# Generated by FakeRAM 2.0
VERSION 5.7 ;
BUSBITCHARS "[]" ;
PROPERTYDEFINITIONS
  MACRO width INTEGER ;
  MACRO depth INTEGER ;
  MACRO banks INTEGER ;
END PROPERTYDEFINITIONS
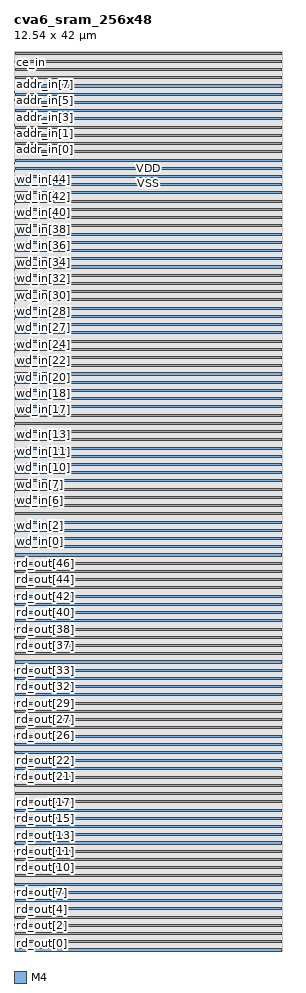
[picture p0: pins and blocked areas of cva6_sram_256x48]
MACRO cva6_sram_256x48
  PROPERTY width 48 ;
  PROPERTY depth 256 ;
  PROPERTY banks 1 ;
  FOREIGN cva6_sram_256x48 0 0 ;
  SYMMETRY X Y R90 ;
  SIZE 12.5400 BY 42.0000 ;
  CLASS BLOCK ;
  PIN rd_out[0]
    DIRECTION OUTPUT ;
    USE SIGNAL ;
    PORT
      LAYER M4 ;
      RECT 0.00000 0.04800 0.02400 0.07200 ;
    END
  END rd_out[0]
  PIN rd_out[1]
    DIRECTION OUTPUT ;
    USE SIGNAL ;
    PORT
      LAYER M4 ;
      RECT 0.00000 0.43200 0.02400 0.45600 ;
    END
  END rd_out[1]
  PIN rd_out[2]
    DIRECTION OUTPUT ;
    USE SIGNAL ;
    PORT
      LAYER M4 ;
      RECT 0.00000 0.81600 0.02400 0.84000 ;
    END
  END rd_out[2]
  PIN rd_out[3]
    DIRECTION OUTPUT ;
    USE SIGNAL ;
    PORT
      LAYER M4 ;
      RECT 0.00000 1.20000 0.02400 1.22400 ;
    END
  END rd_out[3]
  PIN rd_out[4]
    DIRECTION OUTPUT ;
    USE SIGNAL ;
    PORT
      LAYER M4 ;
      RECT 0.00000 1.58400 0.02400 1.60800 ;
    END
  END rd_out[4]
  PIN rd_out[5]
    DIRECTION OUTPUT ;
    USE SIGNAL ;
    PORT
      LAYER M4 ;
      RECT 0.00000 1.96800 0.02400 1.99200 ;
    END
  END rd_out[5]
  PIN rd_out[6]
    DIRECTION OUTPUT ;
    USE SIGNAL ;
    PORT
      LAYER M4 ;
      RECT 0.00000 2.35200 0.02400 2.37600 ;
    END
  END rd_out[6]
  PIN rd_out[7]
    DIRECTION OUTPUT ;
    USE SIGNAL ;
    PORT
      LAYER M4 ;
      RECT 0.00000 2.73600 0.02400 2.76000 ;
    END
  END rd_out[7]
  PIN rd_out[8]
    DIRECTION OUTPUT ;
    USE SIGNAL ;
    PORT
      LAYER M4 ;
      RECT 0.00000 3.12000 0.02400 3.14400 ;
    END
  END rd_out[8]
  PIN rd_out[9]
    DIRECTION OUTPUT ;
    USE SIGNAL ;
    PORT
      LAYER M4 ;
      RECT 0.00000 3.50400 0.02400 3.52800 ;
    END
  END rd_out[9]
  PIN rd_out[10]
    DIRECTION OUTPUT ;
    USE SIGNAL ;
    PORT
      LAYER M4 ;
      RECT 0.00000 3.88800 0.02400 3.91200 ;
    END
  END rd_out[10]
  PIN rd_out[11]
    DIRECTION OUTPUT ;
    USE SIGNAL ;
    PORT
      LAYER M4 ;
      RECT 0.00000 4.27200 0.02400 4.29600 ;
    END
  END rd_out[11]
  PIN rd_out[12]
    DIRECTION OUTPUT ;
    USE SIGNAL ;
    PORT
      LAYER M4 ;
      RECT 0.00000 4.65600 0.02400 4.68000 ;
    END
  END rd_out[12]
  PIN rd_out[13]
    DIRECTION OUTPUT ;
    USE SIGNAL ;
    PORT
      LAYER M4 ;
      RECT 0.00000 5.04000 0.02400 5.06400 ;
    END
  END rd_out[13]
  PIN rd_out[14]
    DIRECTION OUTPUT ;
    USE SIGNAL ;
    PORT
      LAYER M4 ;
      RECT 0.00000 5.42400 0.02400 5.44800 ;
    END
  END rd_out[14]
  PIN rd_out[15]
    DIRECTION OUTPUT ;
    USE SIGNAL ;
    PORT
      LAYER M4 ;
      RECT 0.00000 5.80800 0.02400 5.83200 ;
    END
  END rd_out[15]
  PIN rd_out[16]
    DIRECTION OUTPUT ;
    USE SIGNAL ;
    PORT
      LAYER M4 ;
      RECT 0.00000 6.19200 0.02400 6.21600 ;
    END
  END rd_out[16]
  PIN rd_out[17]
    DIRECTION OUTPUT ;
    USE SIGNAL ;
    PORT
      LAYER M4 ;
      RECT 0.00000 6.57600 0.02400 6.60000 ;
    END
  END rd_out[17]
  PIN rd_out[18]
    DIRECTION OUTPUT ;
    USE SIGNAL ;
    PORT
      LAYER M4 ;
      RECT 0.00000 6.96000 0.02400 6.98400 ;
    END
  END rd_out[18]
  PIN rd_out[19]
    DIRECTION OUTPUT ;
    USE SIGNAL ;
    PORT
      LAYER M4 ;
      RECT 0.00000 7.34400 0.02400 7.36800 ;
    END
  END rd_out[19]
  PIN rd_out[20]
    DIRECTION OUTPUT ;
    USE SIGNAL ;
    PORT
      LAYER M4 ;
      RECT 0.00000 7.72800 0.02400 7.75200 ;
    END
  END rd_out[20]
  PIN rd_out[21]
    DIRECTION OUTPUT ;
    USE SIGNAL ;
    PORT
      LAYER M4 ;
      RECT 0.00000 8.11200 0.02400 8.13600 ;
    END
  END rd_out[21]
  PIN rd_out[22]
    DIRECTION OUTPUT ;
    USE SIGNAL ;
    PORT
      LAYER M4 ;
      RECT 0.00000 8.49600 0.02400 8.52000 ;
    END
  END rd_out[22]
  PIN rd_out[23]
    DIRECTION OUTPUT ;
    USE SIGNAL ;
    PORT
      LAYER M4 ;
      RECT 0.00000 8.88000 0.02400 8.90400 ;
    END
  END rd_out[23]
  PIN rd_out[24]
    DIRECTION OUTPUT ;
    USE SIGNAL ;
    PORT
      LAYER M4 ;
      RECT 0.00000 9.26400 0.02400 9.28800 ;
    END
  END rd_out[24]
  PIN rd_out[25]
    DIRECTION OUTPUT ;
    USE SIGNAL ;
    PORT
      LAYER M4 ;
      RECT 0.00000 9.64800 0.02400 9.67200 ;
    END
  END rd_out[25]
  PIN rd_out[26]
    DIRECTION OUTPUT ;
    USE SIGNAL ;
    PORT
      LAYER M4 ;
      RECT 0.00000 10.03200 0.02400 10.05600 ;
    END
  END rd_out[26]
  PIN rd_out[27]
    DIRECTION OUTPUT ;
    USE SIGNAL ;
    PORT
      LAYER M4 ;
      RECT 0.00000 10.41600 0.02400 10.44000 ;
    END
  END rd_out[27]
  PIN rd_out[28]
    DIRECTION OUTPUT ;
    USE SIGNAL ;
    PORT
      LAYER M4 ;
      RECT 0.00000 10.80000 0.02400 10.82400 ;
    END
  END rd_out[28]
  PIN rd_out[29]
    DIRECTION OUTPUT ;
    USE SIGNAL ;
    PORT
      LAYER M4 ;
      RECT 0.00000 11.18400 0.02400 11.20800 ;
    END
  END rd_out[29]
  PIN rd_out[30]
    DIRECTION OUTPUT ;
    USE SIGNAL ;
    PORT
      LAYER M4 ;
      RECT 0.00000 11.56800 0.02400 11.59200 ;
    END
  END rd_out[30]
  PIN rd_out[31]
    DIRECTION OUTPUT ;
    USE SIGNAL ;
    PORT
      LAYER M4 ;
      RECT 0.00000 11.95200 0.02400 11.97600 ;
    END
  END rd_out[31]
  PIN rd_out[32]
    DIRECTION OUTPUT ;
    USE SIGNAL ;
    PORT
      LAYER M4 ;
      RECT 0.00000 12.33600 0.02400 12.36000 ;
    END
  END rd_out[32]
  PIN rd_out[33]
    DIRECTION OUTPUT ;
    USE SIGNAL ;
    PORT
      LAYER M4 ;
      RECT 0.00000 12.72000 0.02400 12.74400 ;
    END
  END rd_out[33]
  PIN rd_out[34]
    DIRECTION OUTPUT ;
    USE SIGNAL ;
    PORT
      LAYER M4 ;
      RECT 0.00000 13.10400 0.02400 13.12800 ;
    END
  END rd_out[34]
  PIN rd_out[35]
    DIRECTION OUTPUT ;
    USE SIGNAL ;
    PORT
      LAYER M4 ;
      RECT 0.00000 13.48800 0.02400 13.51200 ;
    END
  END rd_out[35]
  PIN rd_out[36]
    DIRECTION OUTPUT ;
    USE SIGNAL ;
    PORT
      LAYER M4 ;
      RECT 0.00000 13.87200 0.02400 13.89600 ;
    END
  END rd_out[36]
  PIN rd_out[37]
    DIRECTION OUTPUT ;
    USE SIGNAL ;
    PORT
      LAYER M4 ;
      RECT 0.00000 14.25600 0.02400 14.28000 ;
    END
  END rd_out[37]
  PIN rd_out[38]
    DIRECTION OUTPUT ;
    USE SIGNAL ;
    PORT
      LAYER M4 ;
      RECT 0.00000 14.64000 0.02400 14.66400 ;
    END
  END rd_out[38]
  PIN rd_out[39]
    DIRECTION OUTPUT ;
    USE SIGNAL ;
    PORT
      LAYER M4 ;
      RECT 0.00000 15.02400 0.02400 15.04800 ;
    END
  END rd_out[39]
  PIN rd_out[40]
    DIRECTION OUTPUT ;
    USE SIGNAL ;
    PORT
      LAYER M4 ;
      RECT 0.00000 15.40800 0.02400 15.43200 ;
    END
  END rd_out[40]
  PIN rd_out[41]
    DIRECTION OUTPUT ;
    USE SIGNAL ;
    PORT
      LAYER M4 ;
      RECT 0.00000 15.79200 0.02400 15.81600 ;
    END
  END rd_out[41]
  PIN rd_out[42]
    DIRECTION OUTPUT ;
    USE SIGNAL ;
    PORT
      LAYER M4 ;
      RECT 0.00000 16.17600 0.02400 16.20000 ;
    END
  END rd_out[42]
  PIN rd_out[43]
    DIRECTION OUTPUT ;
    USE SIGNAL ;
    PORT
      LAYER M4 ;
      RECT 0.00000 16.56000 0.02400 16.58400 ;
    END
  END rd_out[43]
  PIN rd_out[44]
    DIRECTION OUTPUT ;
    USE SIGNAL ;
    PORT
      LAYER M4 ;
      RECT 0.00000 16.94400 0.02400 16.96800 ;
    END
  END rd_out[44]
  PIN rd_out[45]
    DIRECTION OUTPUT ;
    USE SIGNAL ;
    PORT
      LAYER M4 ;
      RECT 0.00000 17.32800 0.02400 17.35200 ;
    END
  END rd_out[45]
  PIN rd_out[46]
    DIRECTION OUTPUT ;
    USE SIGNAL ;
    PORT
      LAYER M4 ;
      RECT 0.00000 17.71200 0.02400 17.73600 ;
    END
  END rd_out[46]
  PIN rd_out[47]
    DIRECTION OUTPUT ;
    USE SIGNAL ;
    PORT
      LAYER M4 ;
      RECT 0.00000 18.09600 0.02400 18.12000 ;
    END
  END rd_out[47]
  PIN wd_in[0]
    DIRECTION INPUT ;
    USE SIGNAL ;
    PORT
      LAYER M4 ;
      RECT 0.00000 18.72000 0.02400 18.74400 ;
    END
  END wd_in[0]
  PIN wd_in[1]
    DIRECTION INPUT ;
    USE SIGNAL ;
    PORT
      LAYER M4 ;
      RECT 0.00000 19.10400 0.02400 19.12800 ;
    END
  END wd_in[1]
  PIN wd_in[2]
    DIRECTION INPUT ;
    USE SIGNAL ;
    PORT
      LAYER M4 ;
      RECT 0.00000 19.48800 0.02400 19.51200 ;
    END
  END wd_in[2]
  PIN wd_in[3]
    DIRECTION INPUT ;
    USE SIGNAL ;
    PORT
      LAYER M4 ;
      RECT 0.00000 19.87200 0.02400 19.89600 ;
    END
  END wd_in[3]
  PIN wd_in[4]
    DIRECTION INPUT ;
    USE SIGNAL ;
    PORT
      LAYER M4 ;
      RECT 0.00000 20.25600 0.02400 20.28000 ;
    END
  END wd_in[4]
  PIN wd_in[5]
    DIRECTION INPUT ;
    USE SIGNAL ;
    PORT
      LAYER M4 ;
      RECT 0.00000 20.64000 0.02400 20.66400 ;
    END
  END wd_in[5]
  PIN wd_in[6]
    DIRECTION INPUT ;
    USE SIGNAL ;
    PORT
      LAYER M4 ;
      RECT 0.00000 21.02400 0.02400 21.04800 ;
    END
  END wd_in[6]
  PIN wd_in[7]
    DIRECTION INPUT ;
    USE SIGNAL ;
    PORT
      LAYER M4 ;
      RECT 0.00000 21.40800 0.02400 21.43200 ;
    END
  END wd_in[7]
  PIN wd_in[8]
    DIRECTION INPUT ;
    USE SIGNAL ;
    PORT
      LAYER M4 ;
      RECT 0.00000 21.79200 0.02400 21.81600 ;
    END
  END wd_in[8]
  PIN wd_in[9]
    DIRECTION INPUT ;
    USE SIGNAL ;
    PORT
      LAYER M4 ;
      RECT 0.00000 22.17600 0.02400 22.20000 ;
    END
  END wd_in[9]
  PIN wd_in[10]
    DIRECTION INPUT ;
    USE SIGNAL ;
    PORT
      LAYER M4 ;
      RECT 0.00000 22.56000 0.02400 22.58400 ;
    END
  END wd_in[10]
  PIN wd_in[11]
    DIRECTION INPUT ;
    USE SIGNAL ;
    PORT
      LAYER M4 ;
      RECT 0.00000 22.94400 0.02400 22.96800 ;
    END
  END wd_in[11]
  PIN wd_in[12]
    DIRECTION INPUT ;
    USE SIGNAL ;
    PORT
      LAYER M4 ;
      RECT 0.00000 23.32800 0.02400 23.35200 ;
    END
  END wd_in[12]
  PIN wd_in[13]
    DIRECTION INPUT ;
    USE SIGNAL ;
    PORT
      LAYER M4 ;
      RECT 0.00000 23.71200 0.02400 23.73600 ;
    END
  END wd_in[13]
  PIN wd_in[14]
    DIRECTION INPUT ;
    USE SIGNAL ;
    PORT
      LAYER M4 ;
      RECT 0.00000 24.09600 0.02400 24.12000 ;
    END
  END wd_in[14]
  PIN wd_in[15]
    DIRECTION INPUT ;
    USE SIGNAL ;
    PORT
      LAYER M4 ;
      RECT 0.00000 24.48000 0.02400 24.50400 ;
    END
  END wd_in[15]
  PIN wd_in[16]
    DIRECTION INPUT ;
    USE SIGNAL ;
    PORT
      LAYER M4 ;
      RECT 0.00000 24.86400 0.02400 24.88800 ;
    END
  END wd_in[16]
  PIN wd_in[17]
    DIRECTION INPUT ;
    USE SIGNAL ;
    PORT
      LAYER M4 ;
      RECT 0.00000 25.24800 0.02400 25.27200 ;
    END
  END wd_in[17]
  PIN wd_in[18]
    DIRECTION INPUT ;
    USE SIGNAL ;
    PORT
      LAYER M4 ;
      RECT 0.00000 25.63200 0.02400 25.65600 ;
    END
  END wd_in[18]
  PIN wd_in[19]
    DIRECTION INPUT ;
    USE SIGNAL ;
    PORT
      LAYER M4 ;
      RECT 0.00000 26.01600 0.02400 26.04000 ;
    END
  END wd_in[19]
  PIN wd_in[20]
    DIRECTION INPUT ;
    USE SIGNAL ;
    PORT
      LAYER M4 ;
      RECT 0.00000 26.40000 0.02400 26.42400 ;
    END
  END wd_in[20]
  PIN wd_in[21]
    DIRECTION INPUT ;
    USE SIGNAL ;
    PORT
      LAYER M4 ;
      RECT 0.00000 26.78400 0.02400 26.80800 ;
    END
  END wd_in[21]
  PIN wd_in[22]
    DIRECTION INPUT ;
    USE SIGNAL ;
    PORT
      LAYER M4 ;
      RECT 0.00000 27.16800 0.02400 27.19200 ;
    END
  END wd_in[22]
  PIN wd_in[23]
    DIRECTION INPUT ;
    USE SIGNAL ;
    PORT
      LAYER M4 ;
      RECT 0.00000 27.55200 0.02400 27.57600 ;
    END
  END wd_in[23]
  PIN wd_in[24]
    DIRECTION INPUT ;
    USE SIGNAL ;
    PORT
      LAYER M4 ;
      RECT 0.00000 27.93600 0.02400 27.96000 ;
    END
  END wd_in[24]
  PIN wd_in[25]
    DIRECTION INPUT ;
    USE SIGNAL ;
    PORT
      LAYER M4 ;
      RECT 0.00000 28.32000 0.02400 28.34400 ;
    END
  END wd_in[25]
  PIN wd_in[26]
    DIRECTION INPUT ;
    USE SIGNAL ;
    PORT
      LAYER M4 ;
      RECT 0.00000 28.70400 0.02400 28.72800 ;
    END
  END wd_in[26]
  PIN wd_in[27]
    DIRECTION INPUT ;
    USE SIGNAL ;
    PORT
      LAYER M4 ;
      RECT 0.00000 29.08800 0.02400 29.11200 ;
    END
  END wd_in[27]
  PIN wd_in[28]
    DIRECTION INPUT ;
    USE SIGNAL ;
    PORT
      LAYER M4 ;
      RECT 0.00000 29.47200 0.02400 29.49600 ;
    END
  END wd_in[28]
  PIN wd_in[29]
    DIRECTION INPUT ;
    USE SIGNAL ;
    PORT
      LAYER M4 ;
      RECT 0.00000 29.85600 0.02400 29.88000 ;
    END
  END wd_in[29]
  PIN wd_in[30]
    DIRECTION INPUT ;
    USE SIGNAL ;
    PORT
      LAYER M4 ;
      RECT 0.00000 30.24000 0.02400 30.26400 ;
    END
  END wd_in[30]
  PIN wd_in[31]
    DIRECTION INPUT ;
    USE SIGNAL ;
    PORT
      LAYER M4 ;
      RECT 0.00000 30.62400 0.02400 30.64800 ;
    END
  END wd_in[31]
  PIN wd_in[32]
    DIRECTION INPUT ;
    USE SIGNAL ;
    PORT
      LAYER M4 ;
      RECT 0.00000 31.00800 0.02400 31.03200 ;
    END
  END wd_in[32]
  PIN wd_in[33]
    DIRECTION INPUT ;
    USE SIGNAL ;
    PORT
      LAYER M4 ;
      RECT 0.00000 31.39200 0.02400 31.41600 ;
    END
  END wd_in[33]
  PIN wd_in[34]
    DIRECTION INPUT ;
    USE SIGNAL ;
    PORT
      LAYER M4 ;
      RECT 0.00000 31.77600 0.02400 31.80000 ;
    END
  END wd_in[34]
  PIN wd_in[35]
    DIRECTION INPUT ;
    USE SIGNAL ;
    PORT
      LAYER M4 ;
      RECT 0.00000 32.16000 0.02400 32.18400 ;
    END
  END wd_in[35]
  PIN wd_in[36]
    DIRECTION INPUT ;
    USE SIGNAL ;
    PORT
      LAYER M4 ;
      RECT 0.00000 32.54400 0.02400 32.56800 ;
    END
  END wd_in[36]
  PIN wd_in[37]
    DIRECTION INPUT ;
    USE SIGNAL ;
    PORT
      LAYER M4 ;
      RECT 0.00000 32.92800 0.02400 32.95200 ;
    END
  END wd_in[37]
  PIN wd_in[38]
    DIRECTION INPUT ;
    USE SIGNAL ;
    PORT
      LAYER M4 ;
      RECT 0.00000 33.31200 0.02400 33.33600 ;
    END
  END wd_in[38]
  PIN wd_in[39]
    DIRECTION INPUT ;
    USE SIGNAL ;
    PORT
      LAYER M4 ;
      RECT 0.00000 33.69600 0.02400 33.72000 ;
    END
  END wd_in[39]
  PIN wd_in[40]
    DIRECTION INPUT ;
    USE SIGNAL ;
    PORT
      LAYER M4 ;
      RECT 0.00000 34.08000 0.02400 34.10400 ;
    END
  END wd_in[40]
  PIN wd_in[41]
    DIRECTION INPUT ;
    USE SIGNAL ;
    PORT
      LAYER M4 ;
      RECT 0.00000 34.46400 0.02400 34.48800 ;
    END
  END wd_in[41]
  PIN wd_in[42]
    DIRECTION INPUT ;
    USE SIGNAL ;
    PORT
      LAYER M4 ;
      RECT 0.00000 34.84800 0.02400 34.87200 ;
    END
  END wd_in[42]
  PIN wd_in[43]
    DIRECTION INPUT ;
    USE SIGNAL ;
    PORT
      LAYER M4 ;
      RECT 0.00000 35.23200 0.02400 35.25600 ;
    END
  END wd_in[43]
  PIN wd_in[44]
    DIRECTION INPUT ;
    USE SIGNAL ;
    PORT
      LAYER M4 ;
      RECT 0.00000 35.61600 0.02400 35.64000 ;
    END
  END wd_in[44]
  PIN wd_in[45]
    DIRECTION INPUT ;
    USE SIGNAL ;
    PORT
      LAYER M4 ;
      RECT 0.00000 36.00000 0.02400 36.02400 ;
    END
  END wd_in[45]
  PIN wd_in[46]
    DIRECTION INPUT ;
    USE SIGNAL ;
    PORT
      LAYER M4 ;
      RECT 0.00000 36.38400 0.02400 36.40800 ;
    END
  END wd_in[46]
  PIN wd_in[47]
    DIRECTION INPUT ;
    USE SIGNAL ;
    PORT
      LAYER M4 ;
      RECT 0.00000 36.76800 0.02400 36.79200 ;
    END
  END wd_in[47]
  PIN addr_in[0]
    DIRECTION INPUT ;
    USE SIGNAL ;
    PORT
      LAYER M4 ;
      RECT 0.00000 37.39200 0.02400 37.41600 ;
    END
  END addr_in[0]
  PIN addr_in[1]
    DIRECTION INPUT ;
    USE SIGNAL ;
    PORT
      LAYER M4 ;
      RECT 0.00000 37.77600 0.02400 37.80000 ;
    END
  END addr_in[1]
  PIN addr_in[2]
    DIRECTION INPUT ;
    USE SIGNAL ;
    PORT
      LAYER M4 ;
      RECT 0.00000 38.16000 0.02400 38.18400 ;
    END
  END addr_in[2]
  PIN addr_in[3]
    DIRECTION INPUT ;
    USE SIGNAL ;
    PORT
      LAYER M4 ;
      RECT 0.00000 38.54400 0.02400 38.56800 ;
    END
  END addr_in[3]
  PIN addr_in[4]
    DIRECTION INPUT ;
    USE SIGNAL ;
    PORT
      LAYER M4 ;
      RECT 0.00000 38.92800 0.02400 38.95200 ;
    END
  END addr_in[4]
  PIN addr_in[5]
    DIRECTION INPUT ;
    USE SIGNAL ;
    PORT
      LAYER M4 ;
      RECT 0.00000 39.31200 0.02400 39.33600 ;
    END
  END addr_in[5]
  PIN addr_in[6]
    DIRECTION INPUT ;
    USE SIGNAL ;
    PORT
      LAYER M4 ;
      RECT 0.00000 39.69600 0.02400 39.72000 ;
    END
  END addr_in[6]
  PIN addr_in[7]
    DIRECTION INPUT ;
    USE SIGNAL ;
    PORT
      LAYER M4 ;
      RECT 0.00000 40.08000 0.02400 40.10400 ;
    END
  END addr_in[7]
  PIN we_in
    DIRECTION INPUT ;
    USE SIGNAL ;
    PORT
      LAYER M4 ;
      RECT 0.00000 40.70400 0.02400 40.72800 ;
    END
  END we_in
  PIN clk
    DIRECTION INPUT ;
    USE SIGNAL ;
    PORT
      LAYER M4 ;
      RECT 0.00000 41.08800 0.02400 41.11200 ;
    END
  END clk
  PIN ce_in
    DIRECTION INPUT ;
    USE SIGNAL ;
    PORT
      LAYER M4 ;
      RECT 0.00000 41.47200 0.02400 41.49600 ;
    END
  END ce_in
  PIN VDD
    DIRECTION INOUT ;
    USE POWER ;
    PORT
      LAYER M4 ;
      RECT 0.04800 0.38400 12.49200 0.48000 ;
      RECT 0.04800 1.15200 12.49200 1.24800 ;
      RECT 0.04800 1.92000 12.49200 2.01600 ;
      RECT 0.04800 2.68800 12.49200 2.78400 ;
      RECT 0.04800 3.45600 12.49200 3.55200 ;
      RECT 0.04800 4.22400 12.49200 4.32000 ;
      RECT 0.04800 4.99200 12.49200 5.08800 ;
      RECT 0.04800 5.76000 12.49200 5.85600 ;
      RECT 0.04800 6.52800 12.49200 6.62400 ;
      RECT 0.04800 7.29600 12.49200 7.39200 ;
      RECT 0.04800 8.06400 12.49200 8.16000 ;
      RECT 0.04800 8.83200 12.49200 8.92800 ;
      RECT 0.04800 9.60000 12.49200 9.69600 ;
      RECT 0.04800 10.36800 12.49200 10.46400 ;
      RECT 0.04800 11.13600 12.49200 11.23200 ;
      RECT 0.04800 11.90400 12.49200 12.00000 ;
      RECT 0.04800 12.67200 12.49200 12.76800 ;
      RECT 0.04800 13.44000 12.49200 13.53600 ;
      RECT 0.04800 14.20800 12.49200 14.30400 ;
      RECT 0.04800 14.97600 12.49200 15.07200 ;
      RECT 0.04800 15.74400 12.49200 15.84000 ;
      RECT 0.04800 16.51200 12.49200 16.60800 ;
      RECT 0.04800 17.28000 12.49200 17.37600 ;
      RECT 0.04800 18.04800 12.49200 18.14400 ;
      RECT 0.04800 18.81600 12.49200 18.91200 ;
      RECT 0.04800 19.58400 12.49200 19.68000 ;
      RECT 0.04800 20.35200 12.49200 20.44800 ;
      RECT 0.04800 21.12000 12.49200 21.21600 ;
      RECT 0.04800 21.88800 12.49200 21.98400 ;
      RECT 0.04800 22.65600 12.49200 22.75200 ;
      RECT 0.04800 23.42400 12.49200 23.52000 ;
      RECT 0.04800 24.19200 12.49200 24.28800 ;
      RECT 0.04800 24.96000 12.49200 25.05600 ;
      RECT 0.04800 25.72800 12.49200 25.82400 ;
      RECT 0.04800 26.49600 12.49200 26.59200 ;
      RECT 0.04800 27.26400 12.49200 27.36000 ;
      RECT 0.04800 28.03200 12.49200 28.12800 ;
      RECT 0.04800 28.80000 12.49200 28.89600 ;
      RECT 0.04800 29.56800 12.49200 29.66400 ;
      RECT 0.04800 30.33600 12.49200 30.43200 ;
      RECT 0.04800 31.10400 12.49200 31.20000 ;
      RECT 0.04800 31.87200 12.49200 31.96800 ;
      RECT 0.04800 32.64000 12.49200 32.73600 ;
      RECT 0.04800 33.40800 12.49200 33.50400 ;
      RECT 0.04800 34.17600 12.49200 34.27200 ;
      RECT 0.04800 34.94400 12.49200 35.04000 ;
      RECT 0.04800 35.71200 12.49200 35.80800 ;
      RECT 0.04800 36.48000 12.49200 36.57600 ;
      RECT 0.04800 37.24800 12.49200 37.34400 ;
      RECT 0.04800 38.01600 12.49200 38.11200 ;
      RECT 0.04800 38.78400 12.49200 38.88000 ;
      RECT 0.04800 39.55200 12.49200 39.64800 ;
      RECT 0.04800 40.32000 12.49200 40.41600 ;
      RECT 0.04800 41.08800 12.49200 41.18400 ;
      RECT 0.04800 41.85600 12.49200 41.95200 ;
    END
  END VDD
  PIN VSS
    DIRECTION INOUT ;
    USE GROUND ;
    PORT
      LAYER M4 ;
      RECT 0.04800 0.00000 12.49200 0.09600 ;
      RECT 0.04800 0.76800 12.49200 0.86400 ;
      RECT 0.04800 1.53600 12.49200 1.63200 ;
      RECT 0.04800 2.30400 12.49200 2.40000 ;
      RECT 0.04800 3.07200 12.49200 3.16800 ;
      RECT 0.04800 3.84000 12.49200 3.93600 ;
      RECT 0.04800 4.60800 12.49200 4.70400 ;
      RECT 0.04800 5.37600 12.49200 5.47200 ;
      RECT 0.04800 6.14400 12.49200 6.24000 ;
      RECT 0.04800 6.91200 12.49200 7.00800 ;
      RECT 0.04800 7.68000 12.49200 7.77600 ;
      RECT 0.04800 8.44800 12.49200 8.54400 ;
      RECT 0.04800 9.21600 12.49200 9.31200 ;
      RECT 0.04800 9.98400 12.49200 10.08000 ;
      RECT 0.04800 10.75200 12.49200 10.84800 ;
      RECT 0.04800 11.52000 12.49200 11.61600 ;
      RECT 0.04800 12.28800 12.49200 12.38400 ;
      RECT 0.04800 13.05600 12.49200 13.15200 ;
      RECT 0.04800 13.82400 12.49200 13.92000 ;
      RECT 0.04800 14.59200 12.49200 14.68800 ;
      RECT 0.04800 15.36000 12.49200 15.45600 ;
      RECT 0.04800 16.12800 12.49200 16.22400 ;
      RECT 0.04800 16.89600 12.49200 16.99200 ;
      RECT 0.04800 17.66400 12.49200 17.76000 ;
      RECT 0.04800 18.43200 12.49200 18.52800 ;
      RECT 0.04800 19.20000 12.49200 19.29600 ;
      RECT 0.04800 19.96800 12.49200 20.06400 ;
      RECT 0.04800 20.73600 12.49200 20.83200 ;
      RECT 0.04800 21.50400 12.49200 21.60000 ;
      RECT 0.04800 22.27200 12.49200 22.36800 ;
      RECT 0.04800 23.04000 12.49200 23.13600 ;
      RECT 0.04800 23.80800 12.49200 23.90400 ;
      RECT 0.04800 24.57600 12.49200 24.67200 ;
      RECT 0.04800 25.34400 12.49200 25.44000 ;
      RECT 0.04800 26.11200 12.49200 26.20800 ;
      RECT 0.04800 26.88000 12.49200 26.97600 ;
      RECT 0.04800 27.64800 12.49200 27.74400 ;
      RECT 0.04800 28.41600 12.49200 28.51200 ;
      RECT 0.04800 29.18400 12.49200 29.28000 ;
      RECT 0.04800 29.95200 12.49200 30.04800 ;
      RECT 0.04800 30.72000 12.49200 30.81600 ;
      RECT 0.04800 31.48800 12.49200 31.58400 ;
      RECT 0.04800 32.25600 12.49200 32.35200 ;
      RECT 0.04800 33.02400 12.49200 33.12000 ;
      RECT 0.04800 33.79200 12.49200 33.88800 ;
      RECT 0.04800 34.56000 12.49200 34.65600 ;
      RECT 0.04800 35.32800 12.49200 35.42400 ;
      RECT 0.04800 36.09600 12.49200 36.19200 ;
      RECT 0.04800 36.86400 12.49200 36.96000 ;
      RECT 0.04800 37.63200 12.49200 37.72800 ;
      RECT 0.04800 38.40000 12.49200 38.49600 ;
      RECT 0.04800 39.16800 12.49200 39.26400 ;
      RECT 0.04800 39.93600 12.49200 40.03200 ;
      RECT 0.04800 40.70400 12.49200 40.80000 ;
      RECT 0.04800 41.47200 12.49200 41.56800 ;
    END
  END VSS
  OBS
    LAYER M1 ;
    RECT 0 0 12.54000 42.00000 ;
    LAYER M2 ;
    RECT 0 0 12.54000 42.00000 ;
    LAYER M3 ;
    RECT 0 0 12.54000 42.00000 ;
    LAYER M4 ;
    RECT 0 0 12.54000 42.00000 ;
  END
END cva6_sram_256x48

END LIBRARY
